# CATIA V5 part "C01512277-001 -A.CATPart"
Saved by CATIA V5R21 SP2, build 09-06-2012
Part number: C01512277-001
Revision: ---
Description: PROPRIETARY NOTICE (do not delete / modify)  ***************************************************************************************************  LA SOCIETE EN COMMANDITE  AIRBUS CANADA  ("AIRBUS CANADA")  PAR  L'INTERMEDIAIRE  DE  SES  DIVISIONS  ET/OU  FILIALES  CORPORATIVES,  FOURNIT  LES PRESENTES  INFORMATIONS  AU  GOUVERNEMENT  A  TITRE CONFIDENTIEL. CES  INFORMATIONS ONT UNE TENEUR CONFIDENTIELLE,  AVEC DROITS DE PROPRIETE,  ET NOUS LES CONSIDERONS  EXCLUS  DE   L'APPLICATION  DE  LA LOI SUR L'ACCES A L'INFORMATION  (CANADA),  LES  LOIS  SUR  L'ACCES  A  L'INFORMATION  EUROPEENNES,  LE FREEDOM OF INFORMATION ACT (ETATS-UNIS) ET D'AUTRES LOIS SEMBLABLES. ELLES  PEUVENT  AUSSI  CONSTITUER DES SECRETS INDUSTRIELS DE NOTRE SOCIETE OU DE TIERCES PARTIES. LA DIVULGATION  PUBLIQUE  DE CES  INFORMATIONS NUIRAIT A AIRBUS CANADA OU A DES TIERCES PARTIES.  CES INFORMATIONS PEUVENT EGALEMENT CONTENIR  DES DONNEES QUI SONT CONTROLEE PAR DES LOIS DE CONTROLE DES EXPORTATIONS DU CANADA, L’EUROPE OU LES  ETATS-  UNIS. TOUTE EXPORTATION OU REEXPORTATION DE DONNEES CONTROLEES SANS AUTORISATION EST STRICTEMENT INTERDITE.  TOUTE INTENTION DE LES DIVULGUER EN TOUT OU EN PARTIE DEVRA ETRE SIGNIFIEE A L'AVANCE ET PAR ECRIT AU VICE-  PRESIDENT, SERVICES JURIDIQUES ET CONFORMITE ET SECRETAIRE CORPORATIF D'AIRBUS CANADA.    AIRBUS CANADA LIMITED PARTNERSHIP  ("AIRBUS CANADA"),  BY ITS AFFILIATES AND/OR SUBSIDIARIES, PROVIDES THIS  INFORMATION TO THE GOVERNMENT IN CONFIDENCE. THIS IS PROPRIETARY CONFIDENTIAL INFORMATION WHICH WE CONSIDER  EXCLUDED  FROM  THE  APPLICATION OF THE ACCESS TO INFORMATION ACT (CANADA),  THE FREEDOM OF INFORMATION ACT  (U.S.A.),  THE ACCESS TO INFORMATION LAWS IN EUROPE, AND OTHER SIMILAR LEGISLATION. AND MAY ALSO CONSTITUTE  TRADE SECRETS OF OUR  COMPANY OR THIRD PARTIES.  PUBLIC  RELEASE  OF  THIS INFORMATION  WOULD BE HARMFUL TO  AIRBUS CANADA OR THIRD PARTIES.  THIS  INFORMATION  MAY  ALSO  CONTAIN DATA THAT IS CONTROLLED BY CANADIAN,  EUROPEAN, OR U.S.A. EXPORT CONTROL LAWS. ANY UNAUTHORIZED EXPORT OR RE-EXPORT OF ANY EXPORT CONTROLLED DATA  IS STRICTLY PROHIBITED  ANY INTENTION TO DISCLOSE SUCH INFORMATION,  OR  PART THEREOF,  MUST BE NOTIFIED IN  ADVANCE AND IN WRITING TO THE VICE PRESIDENT, LEGAL AND COMPLIANCE AND CORPORATE SECRETARY OF AIRBUS CANADA.        LES RENSEIGNEMENTS,  LES DONNEES  ET  DESSINS  TECHNIQUES  DIVULGUES  DANS  LES PRESENTES SONT LA PROPRIETE  EXCLUSIVE DE LA SOCIETE EN COMMANDITE AIRBUS CANADA ("AIRBUS CANADA") OU COMPORTENT DES DROITS DE PROPRIETE  APPARTENANT  A  AUTRUI ET NE PEUVENT ETRE DIVULGUES  A  QUICONQUE  NI  UTILISES PAR QUI QUE CE SOIT SANS LE  CONSENTEMENT  ECRIT  D’AIRBUS  CANADA.  LE DETENTEUR DES  PRESENTES  S'ENGAGE, DANS TOUTES CIRCONSTANCES, A  GARDER CONFIDENTIELS LES DONNEES ET DESSINS TECHNIQUES QU'ELLES CONTIENNENT.   CE QUI PRECEDE NE S'APPLIQUE  PAS  AUX PERSONNES  QUI  ONT DES DROITS DE PROPRIETE SUR CES RENSEIGNEMENTS,  DONNEES TECHNIQUES ET DESSINS  DANS LA MESURE OU CES DROITS EXISTENT.    THE INFORMATION,  TECHNICAL DATA  AND  DESIGNS DISCLOSED HEREIN ARE THE EXCLUSIVE PROPERTY OF AIRBUS CANADA  LIMITED PARTNERSHIP  ("AIRBUS CANADA")  OR  CONTAIN PROPRIETARY RIGHTS OF OTHERS  AND ARE NOT TO BE USED OR  DISCLOSED  TO  OTHERS WITHOUT THE WRITTEN CONSENT OF AIRBUS CANADA.  THE RECIPIENT OF THIS DOCUMENT, BY ITS  RETENTION  AND  USE  AGREES TO  HOLD  IN  CONFIDENCE  THE  TECHNICAL DATA AND DESIGNS CONTAINED HEREIN. THE  FOREGOING SHALL NOT APPLY TO PERSONS HAVING PROPRIETARY RIGHTS TO SUCH INFORMATION,  TECHNICAL DATA OR SUCH  DESIGNS TO THE EXTENT THAT SUCH RIGHTS EXIST.    Copyright 2020 Airbus Canada Limited Partnership. All Rights Reserved.  ***********************************
Property "Title": "TURNBUCKLE, EXT HDL, PASS SVCE DR"
Property "Dataset Type": "DETAIL"
Property "MFG Process": "MACHINED"
Property "Design Authority Program": "BD-500"
Property "Supplier Name And CAGE Code": "AIRBUS CANADA LIMITED PARTNERSHIP L0J48"
Property "Major Supplier Code": "LP"
Property "3D Only": "N/A"
Property "Dimensions": "DIMENSIONS ARE IN INCHES"
Property "Color Coded": "N/A"
Property "Roughness": "ALL MACHINED SURFACES 125 Ra MAX"
Property "Eng. Tolerances": "LINEAR .XX= +/-.03; .XXX= +/-.010; ANGULAR= +/-0.5 DEG"
Property "Tool Design Tolerances": "LINEAR .X= +/-.06; .XX= +/-.015; .XXX= +/-.005; .XXXX= +/-.001; ANGULAR= +/-0.5 DEG"
Property "Material Form": "BAR - ROUND"
Property "Finish Code": "S010"
Property "Wire Gauge": "-"
Property "Form": "N/A"
Property "Type": "N/A"
Property "Style": "N/A"
Property "Density": "N/A"
Property "Material Specification Production": "AMS5659"
Property "Material Description Production": "CRES"
Property "Alloy": "15-5PH"
Property "Material Class": "N/A"
Property "Grade/Composition": "N/A"
Property "Final Condition": "H1025"
Property "Standard Spec Die": "N/A"
Property "Mesh Cell Size": "N/A"
Property "PCCN": "2"
Property "Organization": "DESIGN"
Property "Length": 0
Property "Width": 0
Property "Inside Diameter": 0
Property "Outside Diameter": 0.75
Property "Wall": 0
Property "Thickness": 0
Property "Project": "BA"
Publications: "PartBody", "DATUM_A", "DATUM_B", "DATUM_C"
Material "CRES-PH-15-5-BAR": density 7833.41 kg/m3
Bounding box of the stored display mesh (mm): x -5.512 to 5.512, y -19.812 to 0, z -5.512 to 5.512
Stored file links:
  C:\Users\CQQZ006\Desktop\A220钢钛件\舱门\C01512277-001\C01512277-001 -A.CATPart
  I:\Standard\Materials\Textures\steel100.jpeg

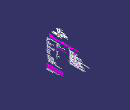
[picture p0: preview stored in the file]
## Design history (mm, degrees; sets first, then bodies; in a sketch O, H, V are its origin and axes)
AxisSystem1: origin (0, 0, 0), X (1, 0, 0), Y (0, 1, 0), Z (0, 0, 1)
TTRSSet1
Part_3D_Annotations1 "CATTPSSet"
Set1 "Geometrical Set for 3D Annotations"
  Set2 "No Show Geometry"
    Extract1 "THREADS": ExtractElem face of Shaft1 from Sketch1.L3
    MultiExtract1 "DATUM_B": ListOfMultiExtractConstraints (MultiExtractConstraint face of Shaft1 from Sketch1.L4; MultiExtractConstraint face of Shaft1 from Sketch1.L4)
    Extract2 "DATUM_A": ExtractElem face of Pocket1 from Sketch2.L3
    Plane1: type Offset, RefPlane zx-plane, Length 9.906 {= (distance(zx-plane,Plane4)) / 2}, reversed
    Plane2: type Offset, RefPlane Plane1, Offset 0.9071
    Plane3: type Offset, RefPlane Plane1, Offset 0.9071, reversed
    Extract3 "DATUM_C": ExtractElem face of Pocket1 from Sketch2.L4
  Set3 "Surfaces for 3D Annotations"
    Split1: ToCut Extract1, Cutting Plane1
    Split2: ToCut Extract1, Cutting (Plane2; Plane3)
Set4 "Construction_Geometry"
  Plane4: type Offset, RefPlane zx-plane, Offset 19.812, reversed
Body1 (main body)
  Sketch1 on yz-plane, origin (0, 0, 0), H (0, 1, 0), V (0, 0, 1)
    line L1 (-19.812, 6.35) -> (0, 6.35)
    line L2 (0, 6.35) -> (0, 2.7051)
    line L3 (0, 2.7051) -> (-19.812, 2.7051)
    line L4 (-19.812, 2.7051) -> (-19.812, 6.35)
    point P3 (0, 2.7051)
    reference intersected line E1 through (0, 0) direction (-1, 0) from xy-plane
    reference intersected line E2 through (-19.812, 0) direction (0, 1) from Plane4
    distance L1 E1 = 6.35
    distance H L3 = 2.7051
    horizontal: L1 H, L3 H
    vertical: L2 V, L4 V
    coincidence: P3 V, E2 L4
  Shaft1: profile Sketch1, axis edge [YZ plane of AxisSystem1 | XY plane of AxisSystem1], angle 360
  Chamfer1: length 5.08, angle 15, on edge [face of Shaft1 from Sketch1.L1 | face of Shaft1 from Sketch1.L2]
  Chamfer2: length 5.08, angle 15, on edge [face of Shaft1 from Sketch1.L4 | face of Shaft1 from Sketch1.L1]
  Body2
    Sketch2 on zx-plane, origin (0, 0, 0), H (-1, 0, 0), V (0, 0, 1)
      line L1 (-5.5118, -5.5118) -> (5.5118, -5.5118)
      line L2 (5.5118, -5.5118) -> (5.5118, 5.5118)
      line L3 (5.5118, 5.5118) -> (-5.5118, 5.5118)
      line L4 (-5.5118, 5.5118) -> (-5.5118, -5.5118)
      reference intersected line E1 through (0, 0) direction (-1, 0) from xy-plane
      construction circle A1 centre (0, 0) radius 5.5118
      circle A2 centre (0, 0) radius 8.89
      distance E1 L1 = 5.5118
      radius A2 = 8.89
      horizontal: L1 H, L3 H
      vertical: L2 V, L4 V
      tangency: A1 L1, L2 A1, L4 A1, L3 A1
    Pocket1: profile Sketch2, direction (0, -1, 0), length 30.48
  Assemble1: tool Body2
  Body3
    Sketch3 on xy-plane, origin (0, 0, 0), H (1, 0, 0), V (0, 1, 0)
      circle A1 centre (0, -12.319) radius 0.9525
      point P1 (0, -12.319)
      reference intersected line E1 through (0, 0) direction (0, 1) from yz-plane
      reference projected point E2 (0, -19.812) from Sketch1.L4
      radius A1 = 0.9525
      distance P1 E2 = 7.493
      coincidence: P1 E1
    Pocket2: profile Sketch3, direction (0, 0, 1), length 30.48, mirrored extent
    Pocket3: profile Sketch4, direction (0, 0, 1), length 30.48, mirrored extent
    Sketch4 on xy-plane, origin (0, 0, 0), H (1, 0, 0), V (0, 1, 0)
      circle A1 centre (0, -7.493) radius 0.9525
      point P1 (0, -7.493)
      reference intersected line E1 through (0, 0) direction (0, 1) from yz-plane
      reference projected point E2 (0, 0) from Sketch1.L2
      radius A1 = 0.9525
      distance E2 P1 = 7.493
      coincidence: E1 P1
  Assemble2: tool Body3
  Body4
    Sketch5 on yz-plane, origin (0, 0, 0), H (0, 1, 0), V (0, 0, 1)
      line L1 (-19.812, -0.8192) -> (-18.3261, -0.8192)
      line L2 (-18.3261, -0.8192) -> (-18.3261, 0.8192)
      line L3 (-18.3261, 0.8192) -> (-19.812, 0.8192)
      line L4 (-19.812, 0.8192) -> (-19.812, -0.8192)
      reference intersected line E1 through (0, 0) direction (-1, 0) from xy-plane
      reference projected line E2 (-19.812, 6.35) -> (-19.812, 3.175) from Sketch1.L4
      line L5 (-1.4859, 0.8192) -> (0, 0.8192)
      line L6 (0, 0.8192) -> (0, -0.8192)
      line L7 (0, -0.8192) -> (-1.4859, -0.8192)
      line L8 (-1.4859, -0.8192) -> (-1.4859, 0.8192)
      distance E1 L3 = 0.8192
      distance L1 L3 = 1.6383
      distance L4 L2 = 1.4859
      distance L6 L8 = 1.4859
      horizontal: L1 H, L3 H, L5 H, L7 H
      vertical: L2 V, L4 V, L6 V, L8 V
      coincidence: L4 E2, L1 L7, L3 L5, V L6
    Pocket4: profile Sketch5, direction (1, 0, 0), length 30.48, mirrored extent
    Fillet1: radius 0.254, on edge [face of Pocket4 from Sketch5.L3 | face of Pocket4 from Sketch5.L2]; edge [face of Pocket4 from Sketch5.L2 | face of Pocket4 from Sketch5.L1]; edge [face of Pocket4 from Sketch5.L8 | face of Pocket4 from Sketch5.L5]; edge [face of Pocket4 from Sketch5.L7 | face of Pocket4 from Sketch5.L8]
  Assemble3: tool Body4
  Chamfer3: length 0.508, angle 45, on edge [face of Shaft1 from Sketch1.L3 | face of Shaft1 from Sketch1.L4] (x2); edge [face of Shaft1 from Sketch1.L2 | face of Shaft1 from Sketch1.L3] (x2)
